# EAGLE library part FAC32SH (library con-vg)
CONNECTOR female, 32 pins, block, type B, rows AC, grid 5.08 mm

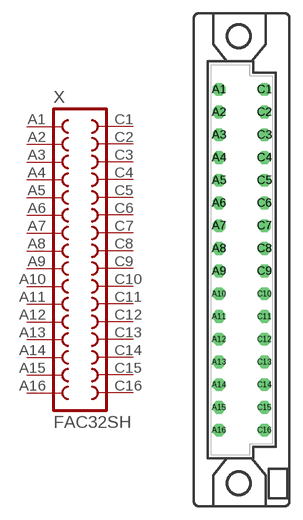
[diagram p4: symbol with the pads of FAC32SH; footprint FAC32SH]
Designator prefix X

## FAC32SH  [FAC32SH]
A1  A1  pas
A2  A2  pas
A3  A3  pas
A4  A4  pas
A5  A5  pas
A6  A6  pas
A7  A7  pas
A8  A8  pas
A9  A9  pas
A10  A10  pas
A11  A11  pas
A12  A12  pas
A13  A13  pas
A14  A14  pas
A15  A15  pas
A16  A16  pas
C1  C1  pas
C2  C2  pas
C3  C3  pas
C4  C4  pas
C5  C5  pas
C6  C6  pas
C7  C7  pas
C8  C8  pas
C9  C9  pas
C10  C10  pas
C11  C11  pas
C12  C12  pas
C13  C13  pas
C14  C14  pas
C15  C15  pas
C16  C16  pas

## Footprint FAC32SH (pad centres in mm)
CONNECTOR female, 32 pins, type B, rows AC, grid 5.08 mm
drill 0.914 octagon: A1 -2.54,19.05; A2 -2.54,16.51; A3 -2.54,13.97; A4 -2.54,11.43; A5 -2.54,8.89; A6 -2.54,6.35; A7 -2.54,3.81; A8 -2.54,1.27; A9 -2.54,-1.27; A10 -2.54,-3.81; A11 -2.54,-6.35; A12 -2.54,-8.89; A13 -2.54,-11.43; A14 -2.54,-13.97; A15 -2.54,-16.51; A16 -2.54,-19.05; C1 2.54,19.05; C2 2.54,16.51; C3 2.54,13.97; C4 2.54,11.43; C5 2.54,8.89; C6 2.54,6.35; C7 2.54,3.81; C8 2.54,1.27; C9 2.54,-1.27; C10 2.54,-3.81; C11 2.54,-6.35; C12 2.54,-8.89; C13 2.54,-11.43; C14 2.54,-13.97; C15 2.54,-16.51; C16 2.54,-19.05
hole 2.794 at -0.305,24.994
hole 2.794 at -0.305,-24.994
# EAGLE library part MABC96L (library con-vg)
CONNECTOR male, 96 pins, block, type C, rows ABC, grid 2.54 mm

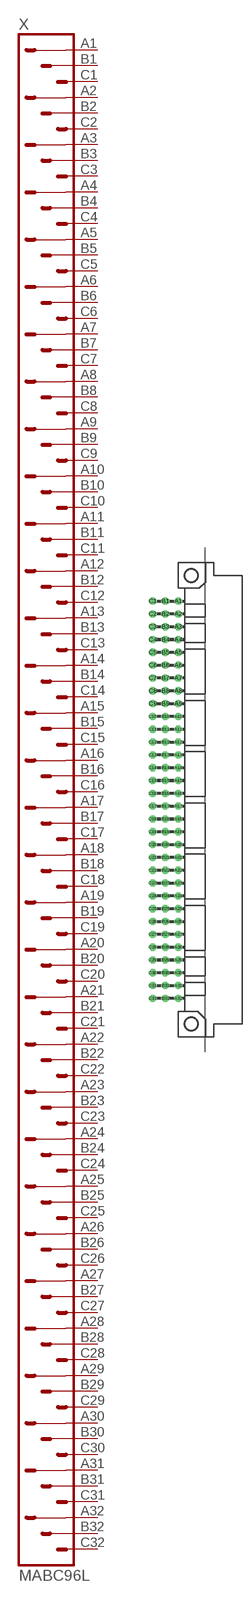
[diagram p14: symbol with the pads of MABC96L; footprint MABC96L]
Designator prefix X

## MABC96L  [MABC96L]
A1  A1  pas
A2  A2  pas
A3  A3  pas
A4  A4  pas
A5  A5  pas
A6  A6  pas
A7  A7  pas
A8  A8  pas
A9  A9  pas
A10  A10  pas
A11  A11  pas
A12  A12  pas
A13  A13  pas
A14  A14  pas
A15  A15  pas
A16  A16  pas
A17  A17  pas
A18  A18  pas
A19  A19  pas
A20  A20  pas
A21  A21  pas
A22  A22  pas
A23  A23  pas
A24  A24  pas
A25  A25  pas
A26  A26  pas
A27  A27  pas
A28  A28  pas
A29  A29  pas
A30  A30  pas
A31  A31  pas
A32  A32  pas
B1  B1  pas
B2  B2  pas
B3  B3  pas
B4  B4  pas
B5  B5  pas
B6  B6  pas
B7  B7  pas
B8  B8  pas
B9  B9  pas
B10  B10  pas
B11  B11  pas
B12  B12  pas
B13  B13  pas
B14  B14  pas
B15  B15  pas
B16  B16  pas
B17  B17  pas
B18  B18  pas
B19  B19  pas
B20  B20  pas
B21  B21  pas
B22  B22  pas
B23  B23  pas
B24  B24  pas
B25  B25  pas
B26  B26  pas
B27  B27  pas
B28  B28  pas
B29  B29  pas
B30  B30  pas
B31  B31  pas
B32  B32  pas
C1  C1  pas
C2  C2  pas
C3  C3  pas
C4  C4  pas
C5  C5  pas
C6  C6  pas
C7  C7  pas
C8  C8  pas
C9  C9  pas
C10  C10  pas
C11  C11  pas
C12  C12  pas
C13  C13  pas
C14  C14  pas
C15  C15  pas
C16  C16  pas
C17  C17  pas
C18  C18  pas
C19  C19  pas
C20  C20  pas
C21  C21  pas
C22  C22  pas
C23  C23  pas
C24  C24  pas
C25  C25  pas
C26  C26  pas
C27  C27  pas
C28  C28  pas
C29  C29  pas
C30  C30  pas
C31  C31  pas
C32  C32  pas

## Footprint MABC96L (pad centres in mm)
CONNECTOR male, 96 pins, type C, rows ABC, grid 2.54 mm
drill 0.914 octagon: A1 -2.54,39.37; A2 -2.54,36.83; A3 -2.54,34.29; A4 -2.54,31.75; A5 -2.54,29.21; A6 -2.54,26.67; A7 -2.54,24.13; A8 -2.54,21.59; A9 -2.54,19.05; A10 -2.54,16.51; A11 -2.54,13.97; A12 -2.54,11.43; A13 -2.54,8.89; A14 -2.54,6.35; A15 -2.54,3.81; A16 -2.54,1.27; A17 -2.54,-1.27; A18 -2.54,-3.81; A19 -2.54,-6.35; A20 -2.54,-8.89; A21 -2.54,-11.43; A22 -2.54,-13.97; A23 -2.54,-16.51; A24 -2.54,-19.05; A25 -2.54,-21.59; A26 -2.54,-24.13; A27 -2.54,-26.67; A28 -2.54,-29.21; A29 -2.54,-31.75; A30 -2.54,-34.29; A31 -2.54,-36.83; A32 -2.54,-39.37; B1 -5.08,39.37; B2 -5.08,36.83; B3 -5.08,34.29; B4 -5.08,31.75; B5 -5.08,29.21; B6 -5.08,26.67; B7 -5.08,24.13; B8 -5.08,21.59; B9 -5.08,19.05; B10 -5.08,16.51; B11 -5.08,13.97; B12 -5.08,11.43; B13 -5.08,8.89; B14 -5.08,6.35; B15 -5.08,3.81; B16 -5.08,1.27; B17 -5.08,-1.27; B18 -5.08,-3.81; B19 -5.08,-6.35; B20 -5.08,-8.89; B21 -5.08,-11.43; B22 -5.08,-13.97; B23 -5.08,-16.51; B24 -5.08,-19.05; B25 -5.08,-21.59; B26 -5.08,-24.13; B27 -5.08,-26.67; B28 -5.08,-29.21; B29 -5.08,-31.75; B30 -5.08,-34.29; B31 -5.08,-36.83; B32 -5.08,-39.37; C1 -7.62,39.37; C2 -7.62,36.83; C3 -7.62,34.29; C4 -7.62,31.75; C5 -7.62,29.21; C6 -7.62,26.67; C7 -7.62,24.13; C8 -7.62,21.59; C9 -7.62,19.05; C10 -7.62,16.51; C11 -7.62,13.97; C12 -7.62,11.43; C13 -7.62,8.89; C14 -7.62,6.35; C15 -7.62,3.81; C16 -7.62,1.27; C17 -7.62,-1.27; C18 -7.62,-3.81; C19 -7.62,-6.35; C20 -7.62,-8.89; C21 -7.62,-11.43; C22 -7.62,-13.97; C23 -7.62,-16.51; C24 -7.62,-19.05; C25 -7.62,-21.59; C26 -7.62,-24.13; C27 -7.62,-26.67; C28 -7.62,-29.21; C29 -7.62,-31.75; C30 -7.62,-34.29; C31 -7.62,-36.83; C32 -7.62,-39.37
hole 2.794 at 0,44.45
hole 2.794 at 0,-44.45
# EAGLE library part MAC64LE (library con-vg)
CONNECTOR male, 64 pins, single, type C, rows AC, grid 5.08 mm

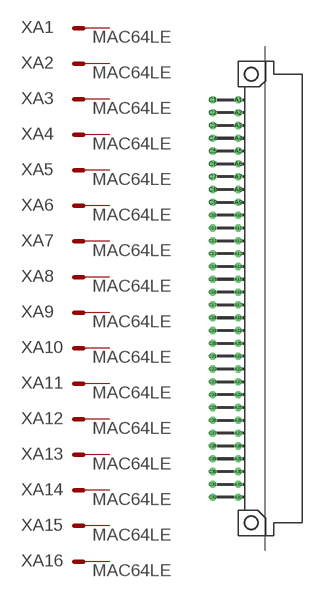
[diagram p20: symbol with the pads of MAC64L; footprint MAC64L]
Designator prefix X; gates A1=M A2=M A3=M A4=M A5=M A6=M A7=M A8=M A9=M A10=M A11=M A12=M A13=M A14=M A15=M A16=M A17=M A18=M A19=M A20=M A21=M A22=M A23=M A24=M A25=M A26=M A27=M A28=M A29=M A30=M A31=M A32=M C1=M C2=M C3=M C4=M C5=M C6=M C7=M C8=M C9=M C10=M C11=M C12=M C13=M C14=M C15=M C16=M C17=M C18=M C19=M C20=M C21=M C22=M C23=M C24=M C25=M C26=M C27=M C28=M C29=M C30=M C31=M C32=M

## MAC64LE  [MAC64L]
A1  A1:S  pas
A2  A2:S  pas
A3  A3:S  pas
A4  A4:S  pas
A5  A5:S  pas
A6  A6:S  pas
A7  A7:S  pas
A8  A8:S  pas
A9  A9:S  pas
A10  A10:S  pas
A11  A11:S  pas
A12  A12:S  pas
A13  A13:S  pas
A14  A14:S  pas
A15  A15:S  pas
A16  A16:S  pas
A17  A17:S  pas
A18  A18:S  pas
A19  A19:S  pas
A20  A20:S  pas
A21  A21:S  pas
A22  A22:S  pas
A23  A23:S  pas
A24  A24:S  pas
A25  A25:S  pas
A26  A26:S  pas
A27  A27:S  pas
A28  A28:S  pas
A29  A29:S  pas
A30  A30:S  pas
A31  A31:S  pas
A32  A32:S  pas
C1  C1:S  pas
C2  C2:S  pas
C3  C3:S  pas
C4  C4:S  pas
C5  C5:S  pas
C6  C6:S  pas
C7  C7:S  pas
C8  C8:S  pas
C9  C9:S  pas
C10  C10:S  pas
C11  C11:S  pas
C12  C12:S  pas
C13  C13:S  pas
C14  C14:S  pas
C15  C15:S  pas
C16  C16:S  pas
C17  C17:S  pas
C18  C18:S  pas
C19  C19:S  pas
C20  C20:S  pas
C21  C21:S  pas
C22  C22:S  pas
C23  C23:S  pas
C24  C24:S  pas
C25  C25:S  pas
C26  C26:S  pas
C27  C27:S  pas
C28  C28:S  pas
C29  C29:S  pas
C30  C30:S  pas
C31  C31:S  pas
C32  C32:S  pas

## Footprint MAC64L (pad centres in mm)
CONNECTOR male, 64 pins, type C, rows AC, grid 5.08 mm
drill 0.914 octagon: A1 -2.54,39.37; A2 -2.54,36.83; A3 -2.54,34.29; A4 -2.54,31.75; A5 -2.54,29.21; A6 -2.54,26.67; A7 -2.54,24.13; A8 -2.54,21.59; A9 -2.54,19.05; A10 -2.54,16.51; A11 -2.54,13.97; A12 -2.54,11.43; A13 -2.54,8.89; A14 -2.54,6.35; A15 -2.54,3.81; A16 -2.54,1.27; A17 -2.54,-1.27; A18 -2.54,-3.81; A19 -2.54,-6.35; A20 -2.54,-8.89; A21 -2.54,-11.43; A22 -2.54,-13.97; A23 -2.54,-16.51; A24 -2.54,-19.05; A25 -2.54,-21.59; A26 -2.54,-24.13; A27 -2.54,-26.67; A28 -2.54,-29.21; A29 -2.54,-31.75; A30 -2.54,-34.29; A31 -2.54,-36.83; A32 -2.54,-39.37; C1 -7.62,39.37; C2 -7.62,36.83; C3 -7.62,34.29; C4 -7.62,31.75; C5 -7.62,29.21; C6 -7.62,26.67; C7 -7.62,24.13; C8 -7.62,21.59; C9 -7.62,19.05; C10 -7.62,16.51; C11 -7.62,13.97; C12 -7.62,11.43; C13 -7.62,8.89; C14 -7.62,6.35; C15 -7.62,3.81; C16 -7.62,1.27; C17 -7.62,-1.27; C18 -7.62,-3.81; C19 -7.62,-6.35; C20 -7.62,-8.89; C21 -7.62,-11.43; C22 -7.62,-13.97; C23 -7.62,-16.51; C24 -7.62,-19.05; C25 -7.62,-21.59; C26 -7.62,-24.13; C27 -7.62,-26.67; C28 -7.62,-29.21; C29 -7.62,-31.75; C30 -7.62,-34.29; C31 -7.62,-36.83; C32 -7.62,-39.37
hole 2.794 at 0,44.45
hole 2.794 at 0,-44.45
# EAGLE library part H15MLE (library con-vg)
CONNECTOR male, 15 high current pins, single, type H, rows DZ

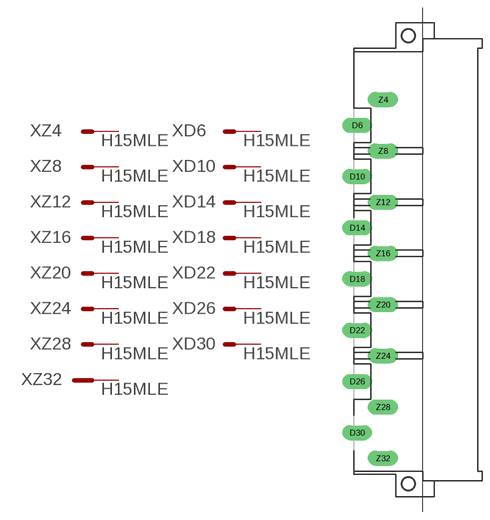
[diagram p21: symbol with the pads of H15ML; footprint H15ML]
Designator prefix X; gates Z4=M Z8=M Z12=M Z16=M Z20=M Z24=M Z28=M D30=M D6=M D10=M D14=M D18=M D22=M D26=M Z32=MG

## H15MLE  [H15ML]
D6  D6:S  pas
D10  D10:S  pas
D14  D14:S  pas
D18  D18:S  pas
D22  D22:S  pas
D26  D26:S  pas
D30  D30:S  pas
Z4  Z4:S  pas
Z8  Z8:S  pas
Z12  Z12:S  pas
Z16  Z16:S  pas
Z20  Z20:S  pas
Z24  Z24:S  pas
Z28  Z28:S  pas
Z32  Z32:S  pas

## Footprint H15ML (pad centres in mm)
CONNECTOR male, 15 pins, type H, rows DZ
drill 1.6 pad 3 long: D6 -10.16,26.67; D10 -10.16,16.51; D14 -10.16,6.35; D18 -10.16,-3.81; D22 -10.16,-13.97; D26 -10.16,-24.13; D30 -10.16,-34.29; Z4 -5.08,31.75; Z8 -5.08,21.59; Z12 -5.08,11.43; Z16 -5.08,1.27; Z20 -5.08,-8.89; Z24 -5.08,-19.05; Z28 -5.08,-29.21; Z32 -5.08,-39.37
hole 2.794 at 0,-44.45
hole 2.794 at 0,44.45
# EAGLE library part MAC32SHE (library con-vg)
CONNECTOR male, 32 pins, single, type C/2, rows AC, grid 5.08 mm

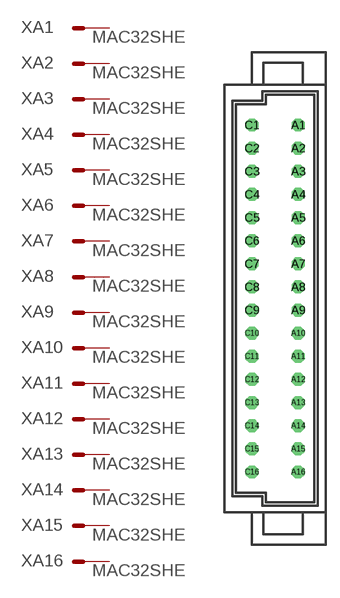
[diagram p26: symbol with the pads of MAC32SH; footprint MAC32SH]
Designator prefix X; gates A1=M A2=M A3=M A4=M A5=M A6=M A7=M A8=M A9=M A10=M A11=M A12=M A13=M A14=M A15=M A16=M C1=M C2=M C3=M C4=M C5=M C6=M C7=M C8=M C9=M C10=M C11=M C12=M C13=M C14=M C15=M C16=M

## MAC32SHE  [MAC32SH]
A1  A1:S  pas
A2  A2:S  pas
A3  A3:S  pas
A4  A4:S  pas
A5  A5:S  pas
A6  A6:S  pas
A7  A7:S  pas
A8  A8:S  pas
A9  A9:S  pas
A10  A10:S  pas
A11  A11:S  pas
A12  A12:S  pas
A13  A13:S  pas
A14  A14:S  pas
A15  A15:S  pas
A16  A16:S  pas
C1  C1:S  pas
C2  C2:S  pas
C3  C3:S  pas
C4  C4:S  pas
C5  C5:S  pas
C6  C6:S  pas
C7  C7:S  pas
C8  C8:S  pas
C9  C9:S  pas
C10  C10:S  pas
C11  C11:S  pas
C12  C12:S  pas
C13  C13:S  pas
C14  C14:S  pas
C15  C15:S  pas
C16  C16:S  pas

## Footprint MAC32SH (pad centres in mm)
CONNECTOR male, 32 pins, type C/2, rows AC, grid 5.08 mm
drill 0.914 octagon: A1 2.54,19.05; A2 2.54,16.51; A3 2.54,13.97; A4 2.54,11.43; A5 2.54,8.89; A6 2.54,6.35; A7 2.54,3.81; A8 2.54,1.27; A9 2.54,-1.27; A10 2.54,-3.81; A11 2.54,-6.35; A12 2.54,-8.89; A13 2.54,-11.43; A14 2.54,-13.97; A15 2.54,-16.51; A16 2.54,-19.05; C1 -2.54,19.05; C2 -2.54,16.51; C3 -2.54,13.97; C4 -2.54,11.43; C5 -2.54,8.89; C6 -2.54,6.35; C7 -2.54,3.81; C8 -2.54,1.27; C9 -2.54,-1.27; C10 -2.54,-3.81; C11 -2.54,-6.35; C12 -2.54,-8.89; C13 -2.54,-11.43; C14 -2.54,-13.97; C15 -2.54,-16.51; C16 -2.54,-19.05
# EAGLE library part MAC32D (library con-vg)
CONNECTOR male, 32 pins, single, type D, rows AC, grid 5.08 mm

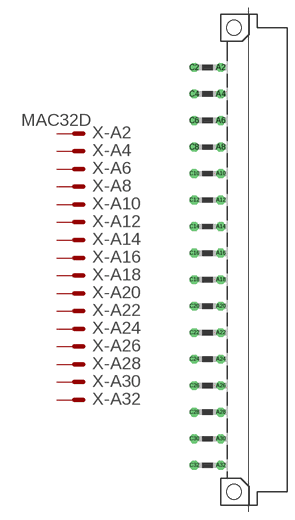
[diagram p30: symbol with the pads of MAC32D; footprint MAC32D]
Designator prefix X; gates -A2=MVAL -A4=MAL -A6=MAL -A8=MAL -A10=MAL -A12=MAL -A14=MAL -A16=MAL -A18=MAL -A20=MAL -A22=MAL -A24=MAL -A26=MAL -A28=MAL -A30=MAL -A32=MAL -C2=MVAL -C4=MAL -C6=MAL -C8=MAL -C10=MAL -C12=MAL -C14=MAL -C16=MAL -C18=MAL -C20=MAL -C22=MAL -C24=MAL -C26=MAL -C28=MAL -C30=MAL -C32=MAL

## MAC32D  [MAC32D]
A2  -A2:S  pas
A4  -A4:S  pas
A6  -A6:S  pas
A8  -A8:S  pas
A10  -A10:S  pas
A12  -A12:S  pas
A14  -A14:S  pas
A16  -A16:S  pas
A18  -A18:S  pas
A20  -A20:S  pas
A22  -A22:S  pas
A24  -A24:S  pas
A26  -A26:S  pas
A28  -A28:S  pas
A30  -A30:S  pas
A32  -A32:S  pas
C2  -C2:S  pas
C4  -C4:S  pas
C6  -C6:S  pas
C8  -C8:S  pas
C10  -C10:S  pas
C12  -C12:S  pas
C14  -C14:S  pas
C16  -C16:S  pas
C18  -C18:S  pas
C20  -C20:S  pas
C22  -C22:S  pas
C24  -C24:S  pas
C26  -C26:S  pas
C28  -C28:S  pas
C30  -C30:S  pas
C32  -C32:S  pas

## Footprint MAC32D (pad centres in mm)
CONNECTOR male, 32 pins, type D, rows AC, grid 5.08 mm
drill 1.118 octagon: A2 -2.54,36.83; A4 -2.54,31.75; A6 -2.54,26.67; A8 -2.54,21.59; A10 -2.54,16.51; A12 -2.54,11.43; A14 -2.54,6.35; A16 -2.54,1.27; A18 -2.54,-3.81; A20 -2.54,-8.89; A22 -2.54,-13.97; A24 -2.54,-19.05; A26 -2.54,-24.13; A28 -2.54,-29.21; A30 -2.54,-34.29; A32 -2.54,-39.37; C2 -7.62,36.83; C4 -7.62,31.75; C6 -7.62,26.67; C8 -7.62,21.59; C10 -7.62,16.51; C12 -7.62,11.43; C14 -7.62,6.35; C16 -7.62,1.27; C18 -7.62,-3.81; C20 -7.62,-8.89; C22 -7.62,-13.97; C24 -7.62,-19.05; C26 -7.62,-24.13; C28 -7.62,-29.21; C30 -7.62,-34.29; C32 -7.62,-39.37
hole 2.794 at 0,44.45
hole 2.794 at 0,-44.45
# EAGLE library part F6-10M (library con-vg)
CONNECTOR female, 6 pins + 10 coax, type C

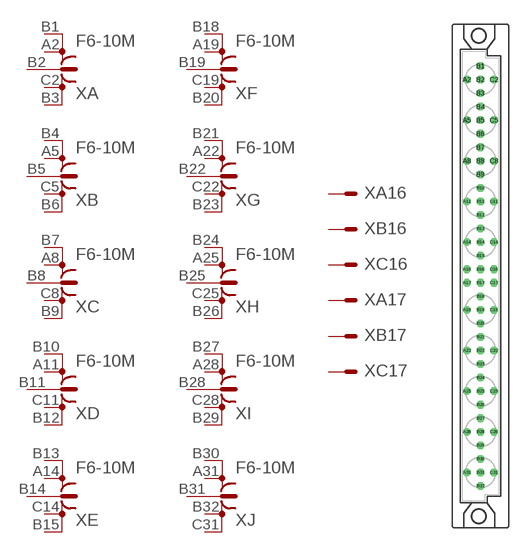
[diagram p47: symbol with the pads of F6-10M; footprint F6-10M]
Designator prefix X; gates A=COAX B=COAX C=COAX D=COAX E=COAX F=COAX G=COAX H=COAX I=COAX J=COAX A16=MAL B16=MAL C16=MAL A17=MAL B17=MAL C17=MAL

## F6-10MF6-10M  [F6-10M]
A2  A:S2  pas
A5  B:S2  pas
A8  C:S2  pas
A11  D:S2  pas
A14  E:S2  pas
A16  A16:S  pas
A17  A17:S  pas
A19  F:S2  pas
A22  G:S2  pas
A25  H:S2  pas
A28  I:S2  pas
A31  J:S2  pas
B1  A:S1  pas
B2  A:S  pas
B3  A:S4  pas
B4  B:S1  pas
B5  B:S  pas
B6  B:S4  pas
B7  C:S1  pas
B8  C:S  pas
B9  C:S4  pas
B10  D:S1  pas
B11  D:S  pas
B12  D:S4  pas
B13  E:S1  pas
B14  E:S  pas
B15  E:S4  pas
B16  B16:S  pas
B17  B17:S  pas
B18  F:S1  pas
B19  F:S  pas
B20  F:S4  pas
B21  G:S1  pas
B22  G:S  pas
B23  G:S4  pas
B24  H:S1  pas
B25  H:S  pas
B26  H:S4  pas
B27  I:S1  pas
B28  I:S  pas
B29  I:S4  pas
B30  J:S1  pas
B31  J:S  pas
B32  J:S3  pas
C2  A:S3  pas
C5  B:S3  pas
C8  C:S3  pas
C11  D:S3  pas
C14  E:S3  pas
C16  C16:S  pas
C17  C17:S  pas
C19  F:S3  pas
C22  G:S3  pas
C25  H:S3  pas
C28  I:S3  pas
C31  J:S4  pas

## Footprint F6-10M (pad centres in mm)
CONNECTOR female, 6 pins + 10 coax, type C
drill 0.914 octagon: A2 -2.54,36.83; A5 -2.54,29.21; A8 -2.54,21.59; A11 -2.54,13.97; A14 -2.54,6.35; A16 -2.54,1.27; A17 -2.54,-1.27; A19 -2.54,-6.35; A22 -2.54,-13.97; A25 -2.54,-21.59; A28 -2.54,-29.21; A31 -2.54,-36.83; B1 0,39.37; B2 0,36.83; B3 0,34.29; B4 0,31.75; B5 0,29.21; B6 0,26.67; B7 0,24.13; B8 0,21.59; B9 0,19.05; B10 0,16.51; B11 0,13.97; B12 0,11.43; B13 0,8.89; B14 0,6.35; B15 0,3.81; B16 0,1.27; B17 0,-1.27; B18 0,-3.81; B19 0,-6.35; B20 0,-8.89; B21 0,-11.43; B22 0,-13.97; B23 0,-16.51; B24 0,-19.05; B25 0,-21.59; B26 0,-24.13; B27 0,-26.67; B28 0,-29.21; B29 0,-31.75; B30 0,-34.29; B31 0,-36.83; B32 0,-39.37; C2 2.54,36.83; C5 2.54,29.21; C8 2.54,21.59; C11 2.54,13.97; C14 2.54,6.35; C16 2.54,1.27; C17 2.54,-1.27; C19 2.54,-6.35; C22 2.54,-13.97; C25 2.54,-21.59; C28 2.54,-29.21; C31 2.54,-36.83
hole 2.794 at -0.305,45.009
hole 2.794 at -0.305,-45.009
